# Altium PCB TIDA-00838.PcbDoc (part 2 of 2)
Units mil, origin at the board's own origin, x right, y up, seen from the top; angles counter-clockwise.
Board outline 1574.8 x 3450 mil, 2 copper layers (Top Layer, Bottom Layer), stack 38.583 mil thick; 90 components, 120 nets, 385 pads, 272 vias.

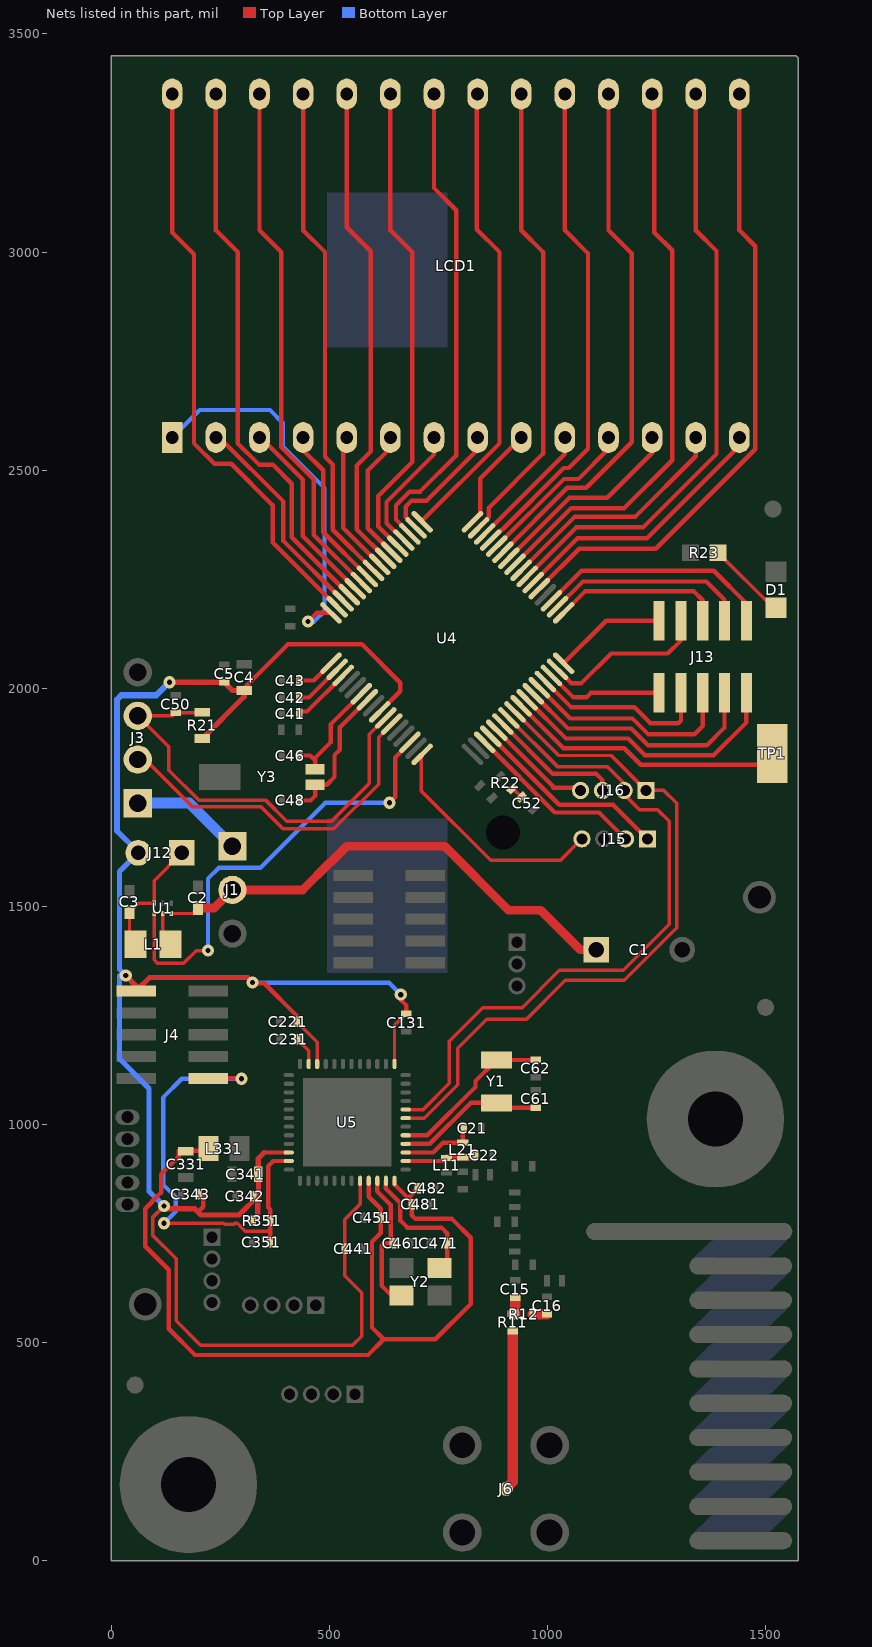
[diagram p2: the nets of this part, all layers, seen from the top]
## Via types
v1: diameter 28, hole 12, Top Layer to Bottom Layer, 238 vias
v2: diameter 39.37, hole 14.96, Top Layer to Bottom Layer, 19 vias
v3: diameter 19.68, hole 7.87, Top Layer to Bottom Layer, 12 vias
v4: diameter 34, hole 16, Top Layer to Bottom Layer, 2 vias
v5: diameter 74.8, hole 59.06, Top Layer to Bottom Layer, 1 vias

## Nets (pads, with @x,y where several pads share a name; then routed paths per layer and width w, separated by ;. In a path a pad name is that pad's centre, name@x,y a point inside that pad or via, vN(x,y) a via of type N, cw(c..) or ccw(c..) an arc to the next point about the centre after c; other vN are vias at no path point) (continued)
NetC15_2: C15.2 R11.1 R12.1 | length 38
  Top Layer w24: R12.1@926,565 C15.2@926,603
NetC16_2: C16.2 R12.2 | length 33
  Top Layer w24: R12.2@966,565 C16.2@999,565
NetC21_2: C21.2 L21.1 U5.3 | length 174.5
  Top Layer w10: U5.3@675,936.26 738.53,936.26 760.74,958.46 L21.1@806,958.46 ; L21.1@806,958.73 806,990.32 C21.2@807.93,992.25
NetC22_1: C22.1 L11.1 L21.2 U5.2 | length 165.6
  Top Layer w10: U5.2@675,916.57 760.57,916.57 L11.1@769,925 ; C22.1@830,925 C22.1@835,930
  Top Layer w14: L11.1@769,925 C22.1@830,925
NetC52_2: C52.2 R22.1 | length 28.7
  Top Layer w8: R22.1@919,1770 921,1770 C52.2@939.86,1751.14
NetC61_1: C61.1 U5.4 Y1.1 | length 341.3
  Top Layer w10: U5.4@675,955.94 730.22,955.94 824.06,1049.79 Y1.1@883,1049.79 893.79,1039 C61.1@973,1039
NetC62_1: C62.1 U5.5 Y1.2 | length 389.3
  Top Layer w10: U5.5@675,975.63 724.63,975.63 835,1086 835,1100 879,1144 Y1.2@896,1144 ; Y1.2@883,1148.21 972.21,1148.21 C62.1@973,1149
NetC231_1: C231.1 U5.23 | length 71.5
  Top Layer w7.87: C231.1@426,1196 452.56,1169.44 U5.23@452.56,1139.01
  Top Layer w10: C231.1@425,1200 C231.1@427.5,1197.5
NetC461_1: C461.1 U5.46 Y2.1 | length 325.7
  Top Layer w10: U5.46@610.04,871.3 610.04,846.96 641,816 641,736 C461.1@643,734 ; C461.1@646,728 625.71,728 619.87,722.17 619.87,631.13 642.5,608.5 Y2.1@665.69,608.5
NetC471_1: C471.1 U5.47 Y2.3 | length 320.1
  Top Layer w10: U5.47@629.72,871.3 629.72,853.28 663,820 663,780 679,764 757.24,764 770,751.24 C471.1@770,728 770,689.19 Y2.3@752.31,671.5 ; Y2.3@741.62,680 Y2.3@741.62,689
NetD1_1: D1.1 R23.2 | length 185.3
  Top Layer w8: R23.2@1390.99,2311 1517.33,2184.66 D1.1@1524,2184.66
NetJ6_1: J6.1 R11.2 | length 368.6
  Top Layer w24: J6.1@905,165 921,181 R11.2@921,527
NRESET: C351.1 J4.10 R351.1 U5.35 | length 1062.8
  Top Layer w8: v1(121,774) 258.41,774 260.28,772.13 281.72,772.13 283.59,774 289,774 307,756 365,756
  Top Layer w10: J4.10@222.68,1106 291,1106 292,1105 v1(299,1105) ; C351.1@365,735 365,756 R351.1@365,780 365,805 360,810 360,905 371.57,916.57 U5.35@407.28,916.57
  Bottom Layer w10: v1(121,774) 147.87,800.87 147.87,834 119,862.87 119,1062 162,1105 v1(299,1105)
P1.2: J16.3 U4.22 | length 305.3
  Top Layer w10: U4.22@897.84,1918.24 1012.08,1804 1112,1804 1126,1790 J16.3@1126,1766
P1.3: J16.4 U4.21 | length 250.9
  Top Layer w10: U4.21@883.92,1904.32 1013.68,1774.56 1013.68,1772 1070,1772 J16.4@1076,1766
P1.4: J15.1 U4.20 | length 456.5
  Top Layer w10: U4.20@870,1890.4 1026.96,1733.44 1150.56,1733.44 J15.1@1229,1655
P1.5: J15.2 U4.19 | length 428
  Top Layer w10: U4.19@856.08,1876.48 1017,1715.57 1118.43,1715.57 J15.2@1179,1655 J15.2@1179,1641.71
P2.5: J13.1 U4.35 | length 546.3
  Top Layer w10: U4.35@1009.19,2200.81 1078.22,2269.83 1381,2269.83 1456,2194.83 J13.1@1456,2155
P2.6: J13.3 U4.34 | length 472.4
  Top Layer w10: U4.34@1023.11,2186.89 1081.23,2245 1364,2245 1406,2203 J13.3@1406,2155
P2.7: J13.5 U4.33 | length 395.4
  Top Layer w10: U4.33@1037.03,2172.97 1087.07,2223 1335,2223 1356,2202 J13.5@1356,2155
P5.0: J13.9 U4.32 | length 259.4
  Top Layer w10: U4.32@1037.03,2057.44 1134.6,2155 J13.9@1256,2155
P5.1: J13.7 U4.31 | length 381.5
  Top Layer w10: U4.31@1023.11,2043.52 1054.63,2012 1078.14,2012 1146.14,2080 1276,2080 1306,2110 J13.7@1306,2155
P5.2: J13.10 U4.30 | length 271.3
  Top Layer w10: U4.30@1009.19,2029.6 1058.79,1980 1090,1980 1099.65,1989.65 J13.10@1256,1989.65
P5.3: J13.8 U4.29 | length 416.5
  Top Layer w10: U4.29@995.27,2015.68 1053.95,1957 1199,1957 1236,1920 1300,1920 1306,1926 J13.8@1306,1989.65
P5.4: J13.6 U4.28 | length 502.8
  Top Layer w10: U4.28@981.36,2001.76 1052.11,1931 1195,1931 1231.5,1894.5 1336.5,1894.5 1356,1914 J13.6@1356,1989.65
P5.5: J13.4 U4.27 | length 584
  Top Layer w10: U4.27@967.44,1987.84 1047.27,1908 1192,1908 1230.5,1869.5 1365.5,1869.5 1406,1910 J13.4@1406,1989.65
P5.6: J13.2 U4.26 | length 653.8
  Top Layer w10: U4.26@953.52,1973.92 1042.44,1885 1185,1885 1223,1847 1381,1847 1456,1922 J13.2@1456,1989.65
P5.7: TP1.1 U4.25 | length 632.8
  Top Layer w10: U4.25@939.6,1960 1036.6,1863 1176,1863 1214,1825 1508,1825 TP1.1@1514,1819
R13: C43.2 U4.1 | length 89.3
  Top Layer w10: C43.2@431,2018 464.48,2018 U4.1@503.92,2057.44
R23: C42.2 U4.2 | length 113.6
  Top Layer w10: C42.2@431,1979 453.32,1979 U4.2@517.84,2043.52
R33: C41.2 U4.3 | length 137.5
  Top Layer w10: C41.2@430.15,1942.85 434.17,1946.87 449.04,1946.87 U4.3@531.76,2029.6
RST/SBWTDIO: C50.1 J3.3 R21.1 U4.10 | length 1015.5
  Top Layer w8: R21.1@209,1945 208,1944 C50.1@148,1944 141,1937 J3.3@61,1937 132,1866 132,1812.44 200.44,1744 353.71,1744 402.71,1695 505,1695 592,1782 592,1894.97 U4.10@629.19,1932.16
S0: LCD1.1 U4.64 | length 872
  Top Layer w10: v1(451,2153) 470.97,2172.97 U4.64@503.92,2172.97
  Bottom Layer w10: LCD1.1@140,2575 203,2638 364,2638 393,2609 393,2555 489,2459 489,2177 465,2153 v1(451,2153)
S1: LCD1.28 U4.63 | length 1354.4
  Top Layer w10: LCD1.28@140,3362.4 140,3045 190,2995 190,2561.58 236.91,2514.66 275.06,2514.66 370,2419.73 370,2334.72 U4.63@517.84,2186.89
S2: LCD1.2 U4.62 | length 499.7
  Top Layer w10: LCD1.2@240,2575 248,2575 394.78,2428.22 394.78,2337.78 U4.62@531.76,2200.81
S3: LCD1.27 U4.61 | length 1292.7
  Top Layer w10: LCD1.27@240,3362.4 240,3050 290,3000 290,2561.58 338.71,2512.86 370.14,2512.86 414,2469 414,2346.4 U4.61@545.68,2214.73
S4: LCD1.3 U4.60 | length 439
  Top Layer w10: LCD1.3@340,2575 342.85,2575 439,2478.85 439,2349.24 U4.60@559.6,2228.64
S5: LCD1.26 U4.59 | length 1216.6
  Top Layer w10: LCD1.26@340,3362.4 340,3050 390,3000 390,2553.13 464,2479.13 464,2352.08 U4.59@573.52,2242.56
S6: LCD1.4 U4.58 | length 379.6
  Top Layer w10: LCD1.4@440,2575 440,2546 486,2500 486,2357.92 U4.58@587.44,2256.48
S7: LCD1.25 U4.57 | length 1158.8
  Top Layer w10: LCD1.25@440,3362.4 440,3050 490,3000 490,2531 508,2513 508,2363.76 U4.57@601.36,2270.4
S8: LCD1.5 U4.56 | length 328.5
  Top Layer w10: LCD1.5@540,2575 532,2567 532,2367.6 U4.56@615.27,2284.32
S9: LCD1.24 U4.55 | length 1127.6
  Top Layer w10: LCD1.24@540,3362.4 540,3057 595,3002 595,2543 563,2511 563,2364.44 U4.55@629.19,2298.24
S10: LCD1.6 U4.54 | length 307
  Top Layer w10: LCD1.6@640,2575 640,2551 588.24,2499.24 588.24,2367.04 U4.54@643.11,2312.16
S11: LCD1.23 U4.53 | length 1108
  Top Layer w10: LCD1.23@640,3362.4 640,3050 690,3000 690,2519 612,2441 612,2371.11 U4.53@657.03,2326.08
S12: LCD1.7 U4.52 | length 281.6
  Top Layer w10: U4.52@659.34,2350.34 631,2378.67 631,2427 740,2536 LCD1.7@740,2575
S13: LCD1.22 U4.51 | length 1114
  Top Layer w10: U4.51@684.87,2353.92 684.87,2355.2 653,2387.07 653,2419.73 684.27,2451 708.18,2451 791,2533.82 791,3096 740,3147 LCD1.22@740,3362.4
S14: LCD1.8 U4.50 | length 305.4
  Top Layer w10: U4.50@698.79,2367.84 698.79,2369.12 675.14,2392.77 675.14,2416.59 688.55,2430 723,2430 840,2547 LCD1.8@840,2575
S15: LCD1.21 U4.49 | length 1076.7
  Top Layer w10: U4.49@712.71,2381.76 712.71,2384.29 890,2561.58 890,3000 837.64,3052.36 837.64,3360.04 LCD1.21@840,3362.4
S16: LCD1.9 U4.48 | length 239.5
  Top Layer w10: U4.48@828.24,2381.76 846,2399.52 846,2481 LCD1.9@940,2575
S17: LCD1.20 U4.47 | length 1076.5
  Top Layer w10: U4.47@842.16,2367.84 842.16,2369.12 865.81,2392.77 865.81,2414 990,2538.19 990,3000 940,3050 LCD1.20@940,3362.4
S18: LCD1.10 U4.46 | length 297.3
  Top Layer w10: U4.46@856.08,2353.92 1040,2537.84 LCD1.10@1040,2575
S19: LCD1.19 U4.45 | length 1144.9
  Top Layer w10: U4.45@870,2340 871.28,2340 894.93,2363.65 896.21,2363.65 1037.56,2505 1049,2505 1093,2549 1093,2997 1040,3050 LCD1.19@1040,3362.4
S20: LCD1.11 U4.44 | length 374.4
  Top Layer w10: U4.44@883.92,2326.08 1037.84,2480 1071,2480 1140,2549 LCD1.11@1140,2575
S21: LCD1.18 U4.43 | length 1219.8
  Top Layer w10: U4.43@897.84,2312.16 1045.68,2460 1089,2460 1193,2564 1193,2997 1140,3050 LCD1.18@1140,3362.4
S22: LCD1.12 U4.42 | length 463.4
  Top Layer w10: U4.42@911.76,2298.24 1050.52,2437 1137,2437 1240,2540 LCD1.12@1240,2575
S23: LCD1.17 U4.41 | length 1317.6
  Top Layer w10: U4.41@925.68,2284.32 1054.48,2413.13 1176.13,2413.13 1286,2523 1286,3004 1245,3045 1245,3357.4 LCD1.17@1240,3362.4
S24: LCD1.13 U4.40 | length 551.8
  Top Layer w10: U4.40@939.6,2270.4 1062.2,2393 1201,2393 1340,2532 LCD1.13@1340,2575
S25: LCD1.16 U4.39 | length 1394.9
  Top Layer w10: U4.39@953.52,2256.48 1066.03,2369 1219,2369 1387.37,2537.37 1387.37,3002.63 1340,3050 LCD1.16@1340,3362.4
S26: LCD1.14 U4.38 | length 621.4
  Top Layer w10: U4.38@967.44,2242.56 1068.87,2344 1228,2344 1440,2556 LCD1.14@1440,2575
S27: LCD1.15 U4.37 | length 1456.9
  Top Layer w10: U4.37@981.36,2228.64 1072.71,2320 1248.42,2320 1476.5,2548.07 1476.5,3013.5 1440,3050 LCD1.15@1440,3362.4
SMCLK: J15.4 U4.16 | length 539.3
  Top Layer w8: U4.16@712.71,1848.64 711.13,1848.64 711.13,1764.87 870,1606 1030,1606 J15.4@1079,1655
STAT: U1.1 U4.14 | length 1057.5
  Top Layer w7.87: U1.1@98.32,1484.98 98.32,1377.49 106.11,1369.69 165.89,1369.69 195.2,1399 v1(222,1399)
  Top Layer w10: v1(638,1738) 651,1751 651,1841.33 684.87,1875.2 U4.14@684.87,1876.48
  Bottom Layer w10: v1(222,1399) 222,1564 247,1589 342,1589 491,1738 v1(638,1738)
SW: L1.1 U1.2 | length 78.5
  Top Layer w8: U1.2@118,1484 118,1431 L1.1@136,1413
TEST/SBWTCK: J3.2 U4.11 | length 810.5
  Top Layer w8: J3.2@61,1837 78,1837 186.87,1728.13 343.87,1728.13 394,1678 510.45,1678 613,1780.55 613,1888.13 U4.11@643.11,1918.24
UART_RX: J16.1 U4.24 U5.7 | length 1593.6
  Top Layer w8: U5.7@675,1015 717.7,1015 794.24,1091.54 794.24,1175.24 861,1242 952,1242 1041,1331 1176,1331 1296,1451 1296,1737 1267,1766 J16.1@1226,1766 1145.87,1846.13 1025.63,1846.13 U4.24@925.68,1946.08
UART_TX: J16.2 U4.23 U5.8 | length 1552.4
  Top Layer w8: U5.8@675,1034.68 714.94,1034.68 775,1094.75 775,1191 852,1268 942,1268 1027.5,1353.5 1173.5,1353.5 1279,1459 1279,1695 1252.29,1721.71 1211,1721.71 1176,1756.71 J16.2@1176,1766 1176,1781.87 1137,1820.87 1023.05,1820.87 U4.23@911.76,1932.16
VCC_430: C4.1 C5.1 C131.1 C221.1 C341.1 C342.1 C343.1 C441.1 J4.1 J12.2 R21.2 R351.2 U4.9 U5.13 U5.22 U5.34 U5.44 | length 5012.5
  Top Layer w7.87: C221.1@425,1236 472.24,1188.76 U5.22@472.24,1139.01 ; U5.13@649.41,1139.01 649.41,1227.41 C131.1@676,1254
  Top Layer w8: v1(121,813.34) 94.87,787.21 94.87,746.39 148.87,692.39 148.87,550.13 204.87,494.13 553.13,494.13 574,515 574,615 535,654 535,782.56 570.67,818.23 U5.44@570.67,871.3
  Top Layer w10: 199,800 211,812 211,840 ; C4.1@305,1995 305,2000.87 405.13,2101 574.73,2101 662.69,2013.03 662.69,1993.5 U4.9@615.27,1946.08 ; v1(324,1326) 326,1324 351,1324 425,1250 C221.1@425,1236 ; 351,936.26 U5.34@407.28,936.26 ; v1(664,1298) 664,1286 676,1274 C131.1@676,1254
  Top Layer w12: v1(33.27,1341.86) 57.32,1317.81 J4.1@57.32,1306 88.32,1337 313,1337 v1(324,1326) ; v1(121,813.34) 127.34,807 192,807 199,800 206,793 293,793 336,836 336,791 R351.2@325,780 ; v1(134,2014) C5.1@259,2014 278,1995 C4.1@305,1995 305,1981 R21.2@209,1885 ; C341.1@337,886 337,922.26 351,936.26 ; 338,833 C341.1@338,886
  Bottom Layer w10: v1(324,1326) 325,1325 637,1325 v1(664,1298)
  Bottom Layer w12: 13.65,1672.98 62,1624.63 J12.2@62,1623 19,1580 19,1356.14 v1(33.27,1341.86) ; 19,1341.86 19,1151 87,1083 87,847.34 v1(121,813.34)
  Bottom Layer w14: 13.65,1672.98 13.65,1974.47 23.53,1984.35 103.35,1984.35 v1@133.5,2014.5
VCC_EXTERN: J1.1 J3.1 | length 258
  Bottom Layer w25: J3.1@61,1737 179,1737 J1.1@278,1638
VCC_IN: C1.1 C2.1 J1.2 U1.3 | length 1136.3
  Top Layer w7.87: U1.3@137.69,1484 186.62,1484 C2.1@199,1496.38
  Top Layer w20: C2.1@199,1496.38 236.38,1496.38 J1.2@278,1538 438.66,1538 502.32,1601.67 503.67,1601.67 540,1638 764.32,1638 910.82,1491.5 984.5,1491.5 1075,1401 C1.1@1112,1401
VDDR: C331.1 C451.1 C481.1 C482.1 L331.2 U5.45 U5.48 | length 2114.6
  Top Layer w8: C481.1@689,817 C481.1@689,823
  Top Layer w10: L331.2@209,945 204,940 155,940 155,927 114.5,886.5 114.5,843.5 113.16,843.5 94.13,824.47 94.13,823.13 78,807 78,721 131.87,667.13 131.87,663.13 132,663 132,532 192,472 589,472 625,508 ; U5.45@590.35,871.3 590.35,834.94 618,807.29 C451.1@618,787 618,751.69 598,731.69 598,535 625,508 ; U5.48@649.41,871.3 649.41,862.59 681.33,830.67 ; C481.1@689,817 689,792.28 697.28,784 781,784 824,741 824,589 743,508 625,508 ; C481.1@689,823 681.33,830.67 ; C482.1@703,854 681.33,832.33 681.33,830.67
VOUT: C3.1 J12.1 L1.2 U1.6 | length 286.3
  Top Layer w7.87: L1.2@56,1413 42,1427 C3.1@42,1486.76 62.87,1507.62 U1.6@98.32,1507.62 98.32,1559.32 J12.1@162,1623
XIN: C48.2 U4.7 Y3.1 | length 326.6
  Top Layer w10: C48.2@431,1743 457,1743 467.5,1753.5 Y3.1@467.5,1779.28 494.28,1779.28 512,1797 512,1847 524,1859 524,1910.48 U4.7@587.44,1973.92
XOUT: C46.2 U4.6 Y3.2 | length 258.1
  Top Layer w10: C46.2@431,1846 456.5,1846 467.5,1835 ; Y3.2@467.5,1814.72 467.5,1835 ; U4.6@573.52,1987.84 502.98,1917.3 502.98,1875.98 467.5,1840.5 467.5,1835
pads on no net: A1. BT1.0 FID1.1 FID2.1 FID3.1 H1.1 H4.1 J4.7 Y3.3
copper on no net:
  other v2: 1344.68,46.34 1541.54,46.34 1344.68,125.08 1541.54,125.08 1344.68,203.82 1541.54,203.82 1344.68,282.56 1541.54,282.56 1344.68,361.3 1541.54,361.3 1344.68,440.04 1541.54,440.04 1344.68,518.78 1541.54,518.78 1344.68,597.52 1541.54,597.52 1344.68,676.26 1541.54,676.26 1541.54,755

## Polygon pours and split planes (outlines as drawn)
GND on Bottom Layer "Bottom Layer-GND_LCD" (solid, remove dead copper, pour order 10): 9,3438 9,2528 1565,2528 1565,3437 8,3437
GND on Bottom Layer "Bottom Layer-GND_FR4133" (solid, remove dead copper, pour order 8): 376,2528 377,2527 377,2087 1565,2087 1565,2529 375,2529
GND on Bottom Layer "Bottom Layer-GND" (hatched 45Degree grid 30 track 8, remove dead copper, pour order 6): 8,2520 16,2528 378,2528 378,2099 392,2085 10,2085 10,2523 12,2525
GND on Bottom Layer "Bottom Layer- GND1310" (solid, remove dead copper, pour order 9): 6,2091 6,13 1069,13 1069,1325 1564,1325 1564,2091 6,2091
GND on Top Layer "Top Layer-GND" (solid, pour order 7): 8,3437 8,12 1071,12 1071,1325 1072,1326 1564,1326 1564,3437 6,3437

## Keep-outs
Keep-Out Layer:
  text ".Layer_Name" at -3173,-1518.49 h60

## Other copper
Top Layer:
  pour cut-out: 539.41,2115.2 770.48,1884.14 1001.54,2115.2 770.48,2346.26 539.41,2115.2 504.2,2115.2 767,2378 777,2378 1035,2120 767,1852 756,1852 499,2109 505.2,2115.2
  region net CAP_EL: 163.66,2148.44 cw(c163.66,2304.07) 8.03,2304.07 cw(c163.66,2304.07) 163.66,2459.71 cw(c163.66,2304.07) 319.29,2304.07 cw(c163.66,2304.07)
  text ".Layer_Name" at -3173,-1518.49 h60
Bottom Layer:
  text ".Layer_Name" at -3173,-1518.49 h60

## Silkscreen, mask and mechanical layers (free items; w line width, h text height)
Top Overlay:
  text ".PRJ_Number" at 884,2427 h42
  text ".PCB_Rev" at 1086,2363 h42
  text ".Layer_Name" at -3173,-1518.49 h60
Bottom Overlay:
  text ".Layer_Name" at -3173,-1518.49 h60
Top Paste:
  text ".Layer_Name" at -3173,-1518.49 h60
Bottom Paste:
  text ".Layer_Name" at -3173,-1518.49 h60
Top Solder:
  text ".Layer_Name" at -3173,-1518.49 h60
  text ".Layer_Name" at -3173,-1518.49 h60
Bottom Solder:
  text ".Layer_Name" at -3173,-1518.49 h60
Drill Guide:
  text ".Layer_Name" at -3173,-1518.49 h60
M1 Board Outline:
  lines w10: 1572,3450 0,3450 0,0 1574.8,0 1574.8,3445.2
  text ".Layer_Name" at -3173,-1518.49 h60
M2 Board Dimensions:
  rectangle: -3625,-1060 -3250,-935
  rectangle: -3750,-935 -3625,-810
  lines w7: -3750,-935 -2750,-935 ; -3625,-1060 -3625,-810 ; -3500,-1060 -3500,-810 ; -3250,-1060 -3250,-810 ; -3000,-1060 -3000,-810 ; -3750,-1060 -3750,-810 -2750,-810 -2750,-1060 -3750,-1060
  lines w10: 0,0 0,3450 ; 1570,4.8 1570,3450
  text ".Layer_Name" at -3173,-1518.49 h60
M3 3D STEP Top:
  text ".Layer_Name" at -3173,-1518.49 h60
M4 3D STEP Bottom:
  text ".Layer_Name" at -3173,-1518.49 h60
M5 Assembly Top:
  lines w10: -4042,-1590.17 2558,-1590.17 ; -4042,-1386.83 2560,-1386.83 ; -4042,-1183.5 -4042,-1793.5 -37,-1793.5 2560,-1793.5 2560,-1183.5 -4041.5,-1183.5 -4041.5,-1793.5 -2466,-1793.5 ; -1577,-1793.5 -1577,-1183.5 ; -310,-1386.83 -310,-1183.5 ; 530,-1386.83 530,-1183.5 ; 1152,-1800 1152,-1597.17
  text "COMPONENTS MARKED 'DNP' SHOULD NOT BE POPULATED." at -2596.5,-978.5 h60
  text "ASSEMBLY VARIANT:" at -2597,-1094 h60
  text ".VariantName" at -1561,-1094 h60
  text "PCB VIEWED FROM TOP SIDE" at -3978.5,-1315.67 h60
  text "BOARD #:" at -1502,-1315.67 h60
  text ".PRJ_Number" at -956.5,-1315.67 h60
  text "REV:" at -112,-1315.67 h60
  text ".PCB_Rev" at 179.5,-1315.67 h60
  text "SVN REV:" at 726,-1315.67 h60
  text ".VersionControl_RevNumber" at 1232,-1315.67 h60
  text "TID #:" at -1502,-1519 h60
  text ".TID" at -956.5,-1519 h60
  text "PLOT NAME =" at -3978.5,-1724.34 h60
  text ".plot_File_Name" at -3173,-1724.34 h60
  text "GENERATED    :" at -1500,-1724.34 h60
  text ".Print_Date" at -630.5,-1724.34 h60
  text ".Print_Time" at 98.5,-1724.34 h60
  text "TEXAS INSTRUMENTS" at 1363,-1724.34 h60
M6 Assembly Bottom:
  lines w10: -4042.5,-1387.33 2559.5,-1387.33 ; -4040.5,-1590.67 2559.5,-1590.67 ; -2634.5,-1800.5 -2634.5,-1597.67 ; -2012.5,-1387.33 -2012.5,-1184 ; -1172.5,-1387.33 -1172.5,-1184 ; 94.5,-1794 94.5,-1184 ; 983.5,-1794 2559,-1794 2559,-1184 -4042.5,-1184 -4042.5,-1794 -1445.5,-1794 2559.5,-1794 2559.5,-1184
  text "COMPONENTS MARKED 'DNP' SHOULD NOT BE POPULATED." at 2352,-978 h60
  text ".VariantName" at 1308,-1094 h60
  text "ASSEMBLY VARIANT:" at 2347,-1094 h60
  text ".VersionControl_RevNumber" at -2714.5,-1316.17 h60
  text "SVN REV:" at -2208.5,-1316.17 h60
  text ".PCB_Rev" at -1662,-1316.17 h60
  text "REV:" at -1370.5,-1316.17 h60
  text ".PRJ_Number" at -526,-1316.17 h60
  text "BOARD #:" at 19.5,-1316.17 h60
  text "PCB VIEWED FROM BOTTOM SIDE" at 2496,-1316.17 h60
  text ".TID" at -526,-1519.5 h60
  text "TID #:" at 19.5,-1519.5 h60
  text "TEXAS INSTRUMENTS" at -2845.5,-1724.84 h60
  text ".Print_Time" at -1581,-1724.84 h60
  text ".Print_Date" at -852,-1724.84 h60
  text "GENERATED    :" at 17.5,-1724.84 h60
  text ".plot_File_Name" at 1690.5,-1724.84 h60
  text "PLOT NAME =" at 2496,-1724.84 h60
M9 Title Sheet:
  drawing of 57 lines, arcs and shapes, not listed
  text "1" at -3010.16,7376.5 h70
  text "2" at -514.5,7376.5 h70
  text "3" at 1974.84,7376.5 h70
  text "4" at 4481.51,7376.5 h70
  text "5" at 6980.5,7376.5 h70
  text "6" at 9485.5,7376.5 h70
  text "A" at -4166.5,6233.5 h70
  text "A" at 10633.5,6233.5 h70
  text "B" at -4166.5,3853.5 h70
  text "B" at 10633.5,3853.5 h70
  text "C" at -4166.5,1478.5 h70
  text "C" at 10633.5,1478.5 h70
  text "PROJECT TITLE:" at 7593.5,-382.5 h45
  text ".PRJ_Title" at 7643.5,-515.83 h70
  text "DESIGNED FOR:" at 7593.5,-683.5 h45
  text ".PRJ_Customer" at 7643.5,-823.5 h70
  text "D" at -4166.5,-891.5 h70
  text "D" at 10633.5,-891.5 h70
  text "FILE NAME:" at 7593.5,-983.5 h45
  text ".PCB_File_Name_No_Path" at 7643.5,-1103.5 h70
  text "Texas Instruments (TI) and/or its licensors do not warrant the accuracy or completeness of this specification" at 2624,-1265.34 h45
  text "ENGINEER:" at 7593.5,-1273.5 h45
  text "LAYOUT BY:" at 9098.5,-1273.5 h45
  text "or any information contained therein. TI and/or its licensors do not warrant that this design will meet" at 2579.01,-1378 h45
  text ".PRJ_Engineer" at 7643.5,-1428.49 h70
  text ".PCB_Layout" at 9149,-1428.49 h70
  text "the specifications, will be suitable for your application or fit for any particular purpose, or will operate in" at 2579.01,-1490.67 h45
  text ".Layer_Name" at -3173,-1518.49 h60
  text "ALTIUM DESIGNER VERSION:" at 9098.5,-1583.5 h45
  text "an implementation. TI and/or its licensors do not warrant that the design is production worthy. You should" at 2579.01,-1603.33 h45
  text "completely validate and test your design implementation to confirm the system functionality for your application." at 2624,-1716 h45
  text ".print_Scale" at 7643.5,-1716.83 h70
  text ".Application_BuildNumber" at 9149,-1716.83 h70
  text "1" at -3010.16,-1923.5 h70
  text "2" at -514.5,-1923.5 h70
  text "3" at 1974.84,-1923.5 h70
  text "4" at 4481.51,-1923.5 h70
  text "5" at 6980.5,-1923.5 h70
  text "6" at 9485.5,-1923.5 h70
M10 Fab Notes:
  drawing of 185 lines, arcs and shapes, not listed
  text "DESIGN INFORMATION" at 8631.02,5250 h60
  text "MIN. TRACK WIDTH:" at 7986.46,5070 h60
  text "8" at 9082.7,5070 h60
  text "MIL" at 9237.46,5070 h60
  text "MIN. CLEARANCE:" at 7986.46,4938 h60
  text "0.2" at 9022.7,4938 h60
  text "mm" at 9237.46,4938 h60
  text "MIN. VIA PAD SIZE:" at 7986.46,4806 h60
  text "24" at 9052.71,4806 h60
  text "MIL" at 9237.46,4806 h60
  text "0.05mm (2MIL)" at 8681.46,4664.29 h60
  text "MINIMUM ANNULAR RING" at 7657.23,4660 h60
  text "EXTERNAL" at 9389.46,4660 h60
  text "PER" at 7857.23,4542 h60
  text "IPC-D-275 CLASS 2 LEVEL C" at 8077.23,4542 h60
  text "MIL, HOLES" at 9565.46,4429.71 h60
  text "+/-" at 9173,4429 h60
  text "+/-" at 10027,4429 h60
  text "REGISTRATION TOLERANCES:" at 7657.23,4424 h60
  text "METAL" at 8857,4424 h60
  text "5" at 9433.2,4424 h60
  text "3" at 10266.2,4424 h60
  text "MIL" at 10382.46,4424 h60
  text "MATERIAL:" at 7582.46,4214.54 h60
  text "FR-4 High Tg" at 8568.9,4074.21 h60
  text "FR-408" at 8003.46,4065.64 h60
  text "X" at 8415.46,4065.64 h60
  text "OTHER" at 9491.46,4065.64 h60
  text "62 MIL (1.6mm) +/-10%" at 8323.56,3902.92 h60
  text "THICKNESS:" at 7657.23,3898.64 h60
  text "X" at 8195.4,3898.64 h60
  text "OTHER" at 9608.46,3898.64 h60
  text "TOLERANCE:" at 7657.23,3740.64 h60
  text "X" at 8496.53,3740.64 h60
  text "ANSI IPC-6012 TYPE 3 CLASS 2" at 8683.48,3740.64 h60
  text "OTHER +/-" at 8683.46,3584.64 h60
  text "BOW & TWIST:" at 7657.23,3427.64 h60
  text "X" at 8496.53,3427.64 h60
  text "ANSI IPC-6012 TYPE 3 CLASS 2" at 8683.48,3427.64 h60
  text "OTHER +/-" at 8683.46,3269.13 h60
  text "DRILLING:" at 7582.46,3130.64 h60
  text "REFERENCE:" at 7657.23,3013.64 h60
  text "X" at 8305.46,3013.64 h60
  text "AS SHOWN" at 8492.46,3013.64 h60
  text "X" at 9206.46,3013.64 h60
  text "NC_DRILL FILES" at 9343.46,3013.64 h60
  text "PTH MIN COPPER THICKNESS:" at 7657.23,2855.64 h60
  text "X" at 9007.46,2855.64 h60
  text "1MIL" at 9144.46,2855.64 h60
  text "OTHER" at 9641.46,2855.64 h60
  text "BOARD FINISH:" at 7582.46,2696.64 h60
  text "SILKSCREEN:" at 7737.68,2578.64 h60
  text "X" at 8686.46,2578.64 h60
  text "TOP" at 8812.46,2578.64 h60
  text "X" at 9196.46,2578.64 h60
  text "BOTTOM" at 9323.46,2578.64 h60
  text "SILKSCREEN COLOR:" at 7737.68,2411.64 h60
  text "X" at 8685.42,2411.64 h60
  text "WHITE" at 8812.46,2411.64 h60
  text "OTHER" at 9323.46,2411.64 h60
  text "SOLDER RESIST COLOR:" at 7737.68,2241.64 h60
  text "X" at 8305.42,2082.44 h60
  text "GREEN" at 8432.46,2082.44 h60
  text "BLUE" at 9023.46,2082.44 h60
  text "OTHER" at 9561.46,2082.44 h60
  text "IMMERSION GOLD (ENIG)" at 8643.46,1893.92 h60
  text "ENEPIG" at 9981,1890.64 h60
  text "SURFACE FINISH:" at 7582.46,1889.64 h60
  text "X" at 8456.51,1889.64 h60
  text "IMM. TIN/SILVER OR EQUIV" at 7912,1732.64 h60
  text "OTHER" at 9343.46,1732.64 h60
  text "ARRAY/PANEL:" at 7582.46,1553.64 h60
  text "CUT AND TRIM PER MECH LAYER 1" at 8643.46,1549.35 h60
  text "N.C. ROUTE" at 8643.46,1397.64 h60
  text "X" at 9322.46,1397.64 h60
  text "V. SCORE" at 9509.46,1397.64 h60
  text "CERTIFICATION:" at 7582.46,1260.64 h60
  text "MATERIALS AND WORKMANSHIP FOR ALL PCBS" at 8307.46,1260.64 h60
  text "TO MEET OR EXCEED THE REQUIREMENTS OF:" at 8307.46,1162.64 h60
  text "X" at 7933.96,1026.13 h60
  text "ANSI IPC-A-600F CLASS ->" at 8072.96,1026.13 h60
  text "X" at 9712.02,1026.13 h60
  text "2" at 9830.96,1026.14 h60
  text "1" at 9515.96,1024.64 h60
  text "3" at 10184.96,1024.64 h60
  text "X" at 7936.02,866.64 h60
  text "UL 94V-0" at 8072.96,866.64 h60
  text "X" at 8748.02,866.64 h60
  text "RoHS" at 8884.96,866.64 h60
  text "OTHER" at 9529.36,866.64 h60
  text "PER ORDER" at 9926.42,866.64 h60
  text "ADDITIONAL REQUIREMENTS:" at 7582.46,725.64 h60
  text "MICROSECTION:" at 7657.23,610.64 h60
  text "YES" at 8562.96,610.64 h60
  text "REQUIRED" at 9424.46,454.49 h60
  text "BARE BOARD ELEC. TEST:" at 7657.23,451.64 h60
  text "NONE" at 8962.96,451.64 h60
  text "X" at 9297.46,451.64 h60
  text "PER ORDER" at 10016.46,451.64 h60
  text "MANUFACTURER'S UL:" at 7657.23,294.64 h60
  text "RAIL" at 8822.96,290.35 h60
  text "METAL" at 9314.77,290.35 h60
  text "X" at 9690,290 h60
  text "SILK" at 9826.46,290.35 h60
  text ".Layer_Name" at -3173,-1518.49 h60
M11 Gerber Information:
  lines w10: -4042,-1590.17 2558,-1590.17 ; -4042,-1386.83 2560,-1386.83 ; -4042,-1183.5 -4042,-1793.5 -37,-1793.5 2560,-1793.5 2560,-1183.5 -4041.5,-1183.5 -4041.5,-1793.5 -2466,-1793.5 ; -1577,-1793.5 -1577,-1183.5 ; -310,-1386.83 -310,-1183.5 ; 530,-1386.83 530,-1183.5 ; 1152,-1800 1152,-1597.17
  text "ALL ARTWORK VIEWED FROM TOP SIDE" at -3978.5,-1315.67 h60
  text "BOARD #:" at -1502,-1315.67 h60
  text ".PRJ_Number" at -956.5,-1315.67 h60
  text "REV:" at -112,-1315.67 h60
  text ".PCB_Rev" at 179.5,-1315.67 h60
  text "SVN REV:" at 726,-1315.67 h60
  text ".VersionControl_RevNumber" at 1232,-1315.67 h60
  text "LAYER NAME =" at -3978.5,-1518.49 h60
  text "TID #:" at -1502,-1519 h60
  text ".TID" at -956.5,-1519 h60
  text "PLOT NAME =" at -3978.5,-1724.34 h60
  text ".plot_File_Name" at -3173,-1724.34 h60
  text "GENERATED    :" at -1500,-1724.34 h60
  text ".Print_Date" at -630.5,-1724.34 h60
  text ".Print_Time" at 98.5,-1724.34 h60
  text "TEXAS INSTRUMENTS" at 1363,-1724.34 h60
M12 Stackup:
  drawing of 191 lines, arcs and shapes, not listed
  text "Layer" at 6040.34,7170 h60
  text "Name" at 6450.26,7170 h60
  text "Material" at 7380,7170 h60
  text "Thickness" at 8239.77,7170 h60
  text "Constant" at 8889.6,7170 h60
  text "Board Layer Stack" at 9459.46,7170 h60
  text "1" at 6040.34,7050 h60
  text "Top Overlay" at 6450.26,7050 h60
  text "2" at 6040.34,6930 h60
  text "Top Solder" at 6450.26,6930 h60
  text "Solder Resist" at 7380,6930 h60
  text "0.40mil" at 8239.77,6930 h60
  text "3.5" at 8889.6,6930 h60
  text "3" at 6040.34,6810 h60
  text "Top Layer" at 6450.26,6810 h60
  text "Copper" at 7380,6810 h60
  text "1.40mil" at 8239.77,6810 h60
  text "4" at 6040.34,6690 h60
  text "Dielectric1" at 6450.26,6690 h60
  text "FR-4" at 7380,6690 h60
  text "59.20mil" at 8239.77,6690 h60
  text "4.8" at 8889.6,6690 h60
  text "5" at 6040.34,6570 h60
  text "Bottom Layer" at 6450.26,6570 h60
  text "Copper" at 7380,6570 h60
  text "1.40mil" at 8239.77,6570 h60
  text "6" at 6040.34,6450 h60
  text "Bottom Solder" at 6450.26,6450 h60
  text "Solder Resist" at 7380,6450 h60
  text "0.40mil" at 8239.77,6450 h60
  text "3.5" at 8889.6,6450 h60
  text "7" at 6040.34,6330 h60
  text "Bottom Overlay" at 6450.26,6330 h60
  text ".Layer_Name" at -3173,-1518.49 h60
M13 Component Bodies Top:
  text ".Layer_Name" at -3173,-1518.49 h60
M14 Component Bodies Bottom:
  text ".Layer_Name" at -3173,-1518.49 h60
M15 Courtyards Top:
  text ".Layer_Name" at -3173,-1518.49 h60
M16 Courtyards Bottom:
  text ".Layer_Name" at -3173,-1518.49 h60
Drill Drawing:
  drawing of 166 lines, arcs and shapes, not listed
  text "Symbol" at 1939.59,2685.48 h72
  text "Quantity" at 2265.16,2685.48 h72
  text "Finished Hole Size" at 2622.16,2685.48 h72
  text "Plated" at 3283.72,2685.48 h72
  text "Hole Type" at 3567.86,2685.48 h72
  text "1" at 2265.16,2536.16 h60
  text "78.50mil (1.994mm)" at 2622.16,2536.16 h60
  text "NPTH" at 3283.72,2536.16 h60
  text "Round" at 3567.86,2536.16 h60
  text "12" at 2265.16,2386.84 h60
  text "7.87mil (0.200mm)" at 2622.16,2386.84 h60
  text "PTH" at 3283.72,2386.84 h60
  text "Round" at 3567.86,2386.84 h60
  text "238" at 2265.16,2237.52 h60
  text "12.00mil (0.305mm)" at 2622.16,2237.52 h60
  text "PTH" at 3283.72,2237.52 h60
  text "Round" at 3567.86,2237.52 h60
  text "19" at 2265.16,2088.2 h60
  text "14.96mil (0.380mm)" at 2622.16,2088.2 h60
  text "PTH" at 3283.72,2088.2 h60
  text "Round" at 3567.86,2088.2 h60
  text "2" at 2265.16,1938.88 h60
  text "16.00mil (0.406mm)" at 2622.16,1938.88 h60
  text "PTH" at 3283.72,1938.88 h60
  text "Round" at 3567.86,1938.88 h60
  text "23" at 2265.16,1789.56 h60
  text "25.59mil (0.650mm)" at 2622.16,1789.56 h60
  text "PTH" at 3283.72,1789.56 h60
  text "Round" at 3567.86,1789.56 h60
  text "5" at 2265.16,1640.24 h60
  text "27.56mil (0.700mm)" at 2622.16,1640.24 h60
  text "PTH" at 3283.72,1640.24 h60
  text "Round" at 3567.86,1640.24 h60
  text "28" at 2265.16,1490.92 h60
  text "29.53mil (0.750mm)" at 2622.16,1490.92 h60
  text "PTH" at 3283.72,1490.92 h60
  text "Round" at 3567.86,1490.92 h60
  text "2" at 2265.16,1341.6 h60
  text "33.46mil (0.850mm)" at 2622.16,1341.6 h60
  text "PTH" at 3283.72,1341.6 h60
  text "Round" at 3567.86,1341.6 h60
  text "2" at 2265.16,1192.28 h60
  text "35.43mil (0.900mm)" at 2622.16,1192.28 h60
  text "PTH" at 3283.72,1192.28 h60
  text "Round" at 3567.86,1192.28 h60
  text "7" at 2265.16,1042.96 h60
  text "40.00mil (1.016mm)" at 2622.16,1042.96 h60
  text "PTH" at 3283.72,1042.96 h60
  text "Round" at 3567.86,1042.96 h60
  text "2" at 2265.16,893.64 h60
  text "52.00mil (1.321mm)" at 2622.16,893.64 h60
  text "PTH" at 3283.72,893.64 h60
  text "Round" at 3567.86,893.64 h60
  text "5" at 2265.16,744.32 h60
  text "59.06mil (1.500mm)" at 2622.16,744.32 h60
  text "PTH" at 3283.72,744.32 h60
  text "Round" at 3567.86,744.32 h60
  text "2" at 2265.16,595 h60
  text "125.98mil (3.200mm)" at 2622.16,595 h60
  text "PTH" at 3283.72,595 h60
  text "Round" at 3567.86,595 h60
  text "348 Total" at 2265.16,445.68 h60
  text ".Layer_Name" at -3173,-1518.49 h60

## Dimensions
-3750,-1060 to -2750,-1060 on M2 Board Dimensions
0,-93 to 1575,-177 on M2 Board Dimensions
0,0 to -263,3453 on M2 Board Dimensions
